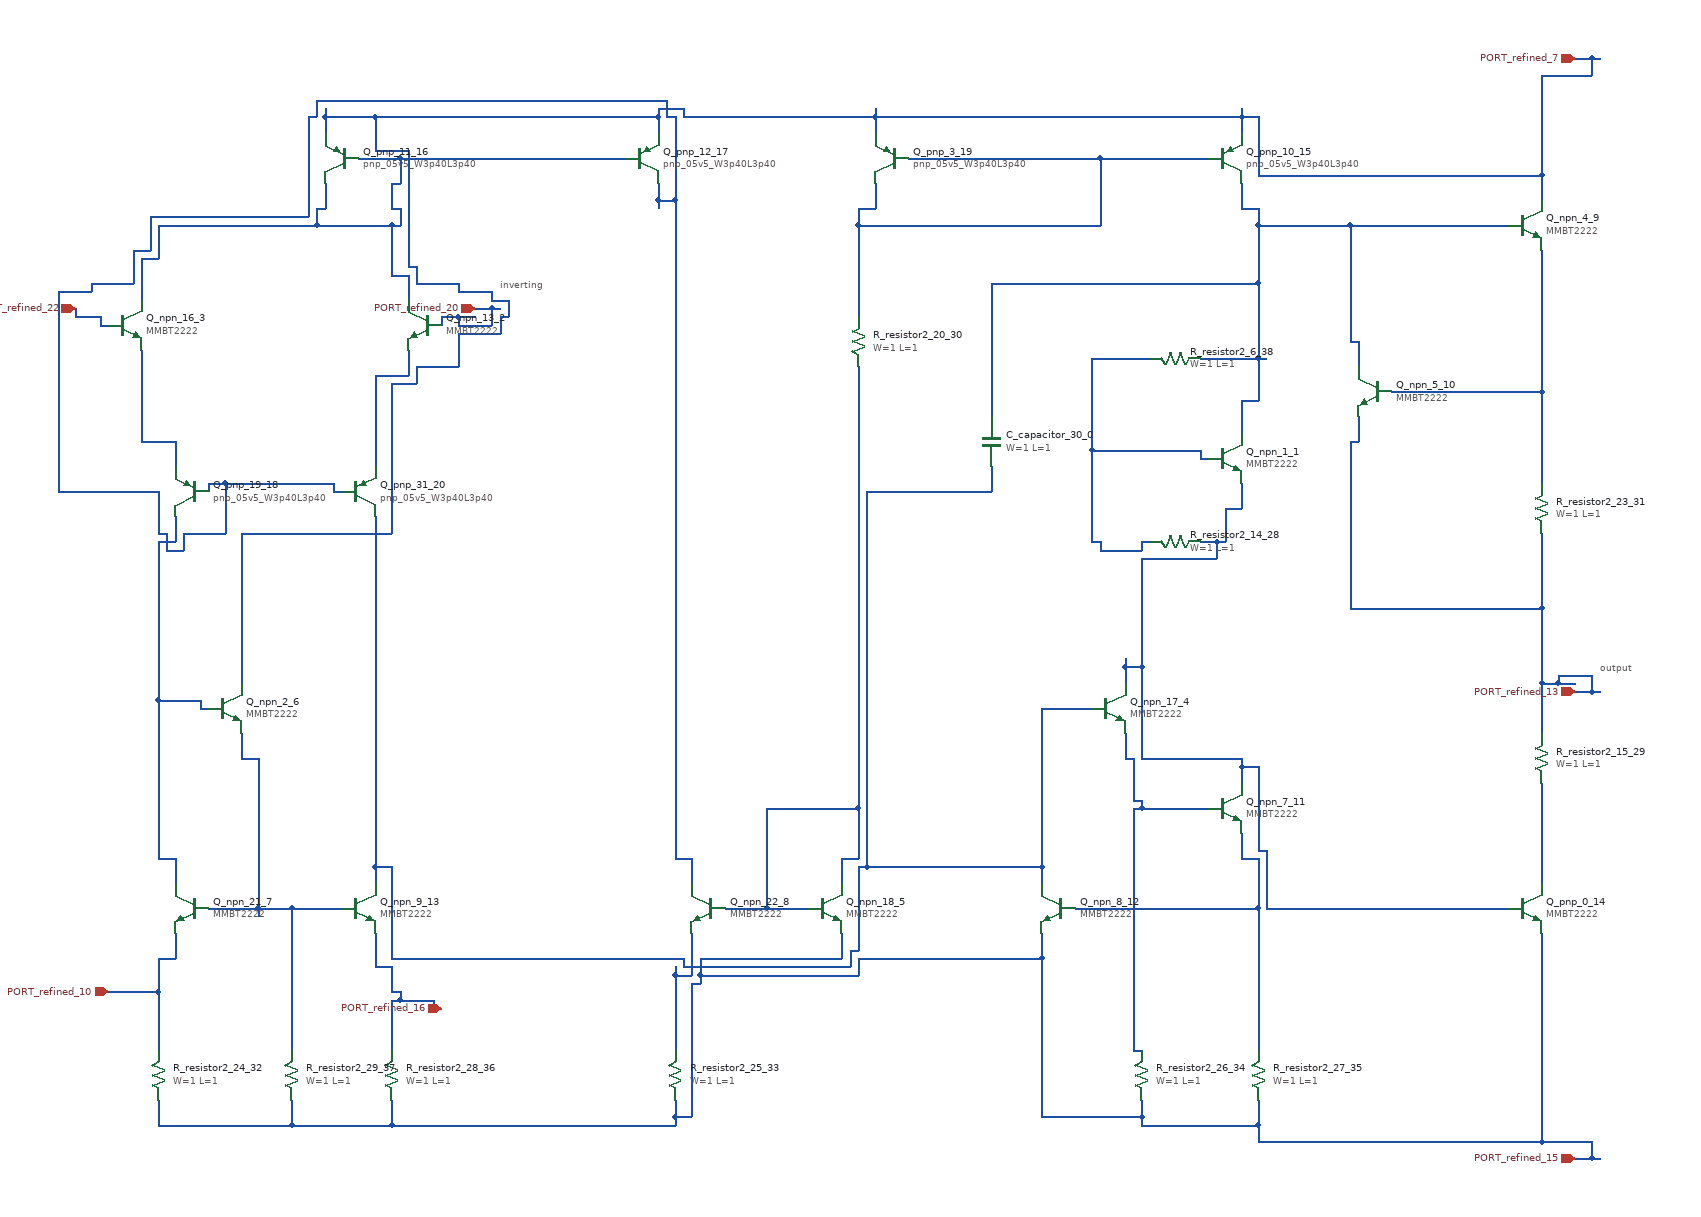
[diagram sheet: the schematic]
v {xschem version=3.4.8 file_version=1.2}
G {}
K {}
V {}
S {}
E {}
C {sky130_fd_pr/cap_mim_m3_1.sym} 1320 520 2 0 {name="C_capacitor_30_0" model=cap_mim_m3_1 W=1 L=1 MF=1 spiceprefix=X}
C {devices/npn.sym} 1600 540 0 0 {name="Q_npn_1_1"
model=MMBT2222
device=MMBT2222
footprint=SOT23
area=1
m=1}
C {devices/npn.sym} 640 380 0 1 {name="Q_npn_13_2"
model=MMBT2222
device=MMBT2222
footprint=SOT23
area=1
m=1}
C {devices/npn.sym} 280 380 0 0 {name="Q_npn_16_3"
model=MMBT2222
device=MMBT2222
footprint=SOT23
area=1
m=1}
C {devices/npn.sym} 1460 840 0 0 {name="Q_npn_17_4"
model=MMBT2222
device=MMBT2222
footprint=SOT23
area=1
m=1}
C {devices/npn.sym} 1120 1080 0 0 {name="Q_npn_18_5"
model=MMBT2222
device=MMBT2222
footprint=SOT23
area=1
m=1}
C {devices/npn.sym} 400 840 0 0 {name="Q_npn_2_6"
model=MMBT2222
device=MMBT2222
footprint=SOT23
area=1
m=1}
C {devices/npn.sym} 360 1080 0 1 {name="Q_npn_21_7"
model=MMBT2222
device=MMBT2222
footprint=SOT23
area=1
m=1}
C {devices/npn.sym} 980 1080 0 1 {name="Q_npn_22_8"
model=MMBT2222
device=MMBT2222
footprint=SOT23
area=1
m=1}
C {devices/npn.sym} 1960 260 0 0 {name="Q_npn_4_9"
model=MMBT2222
device=MMBT2222
footprint=SOT23
area=1
m=1}
C {devices/npn.sym} 1780 460 0 1 {name="Q_npn_5_10"
model=MMBT2222
device=MMBT2222
footprint=SOT23
area=1
m=1}
C {devices/npn.sym} 1600 960 0 0 {name="Q_npn_7_11"
model=MMBT2222
device=MMBT2222
footprint=SOT23
area=1
m=1}
C {devices/npn.sym} 1400 1080 0 1 {name="Q_npn_8_12"
model=MMBT2222
device=MMBT2222
footprint=SOT23
area=1
m=1}
C {devices/npn.sym} 560 1080 0 0 {name="Q_npn_9_13"
model=MMBT2222
device=MMBT2222
footprint=SOT23
area=1
m=1}
C {devices/npn.sym} 1960 1080 0 0 {name="Q_pnp_0_14"
model=MMBT2222
device=MMBT2222
footprint=SOT23
area=1
m=1}
C {sky130_fd_pr/pnp_05v5.sym} 1600 180 0 0 {name="Q_pnp_10_15"
model=pnp_05v5_W3p40L3p40
m=1
spiceprefix=X
}
C {sky130_fd_pr/pnp_05v5.sym} 540 180 0 1 {name="Q_pnp_11_16"
model=pnp_05v5_W3p40L3p40
m=1
spiceprefix=X
}
C {sky130_fd_pr/pnp_05v5.sym} 900 180 0 0 {name="Q_pnp_12_17"
model=pnp_05v5_W3p40L3p40
m=1
spiceprefix=X
}
C {sky130_fd_pr/pnp_05v5.sym} 360 580 0 1 {name="Q_pnp_19_18"
model=pnp_05v5_W3p40L3p40
m=1
spiceprefix=X
}
C {sky130_fd_pr/pnp_05v5.sym} 1200 180 0 1 {name="Q_pnp_3_19"
model=pnp_05v5_W3p40L3p40
m=1
spiceprefix=X
}
C {sky130_fd_pr/pnp_05v5.sym} 560 580 0 0 {name="Q_pnp_31_20"
model=pnp_05v5_W3p40L3p40
m=1
spiceprefix=X
}
C {devices/ipin.sym} 2020 60 0 0 {name="p_port_32_21" lab="PORT_refined_7"}
C {devices/ipin.sym} 260 1180 0 0 {name="p_port_33_22" lab="PORT_refined_10"}
C {devices/ipin.sym} 2020 1380 0 0 {name="p_port_34_23" lab="PORT_refined_15"}
C {devices/ipin.sym} 220 360 0 0 {name="p_port_35_24" lab="PORT_refined_22"}
C {devices/ipin.sym} 660 1200 0 0 {name="p_port_36_25" lab="PORT_refined_16"}
C {devices/ipin.sym} 700 360 0 0 {name="p_port_40_26" lab="PORT_refined_20"}
T {inverting} 730 320 0 0 0.25 0.25 {}
C {devices/ipin.sym} 2020 820 0 0 {name="p_port_41_27" lab="PORT_refined_13"}
T {output} 2050 780 0 0 0.25 0.25 {}
C {sky130_fd_pr/res_generic_po.sym} 1540 640 1 0 {name="R_resistor2_14_28"
W=1
L=1
model=res_generic_po
spiceprefix=X
mult=1}
C {sky130_fd_pr/res_generic_po.sym} 1980 900 2 0 {name="R_resistor2_15_29"
W=1
L=1
model=res_generic_po
spiceprefix=X
mult=1}
C {sky130_fd_pr/res_generic_po.sym} 1160 400 2 0 {name="R_resistor2_20_30"
W=1
L=1
model=res_generic_po
spiceprefix=X
mult=1}
C {sky130_fd_pr/res_generic_po.sym} 1980 600 2 0 {name="R_resistor2_23_31"
W=1
L=1
model=res_generic_po
spiceprefix=X
mult=1}
C {sky130_fd_pr/res_generic_po.sym} 320 1280 2 0 {name="R_resistor2_24_32"
W=1
L=1
model=res_generic_po
spiceprefix=X
mult=1}
C {sky130_fd_pr/res_generic_po.sym} 940 1280 2 0 {name="R_resistor2_25_33"
W=1
L=1
model=res_generic_po
spiceprefix=X
mult=1}
C {sky130_fd_pr/res_generic_po.sym} 1500 1280 2 0 {name="R_resistor2_26_34"
W=1
L=1
model=res_generic_po
spiceprefix=X
mult=1}
C {sky130_fd_pr/res_generic_po.sym} 1640 1280 2 0 {name="R_resistor2_27_35"
W=1
L=1
model=res_generic_po
spiceprefix=X
mult=1}
C {sky130_fd_pr/res_generic_po.sym} 600 1280 2 0 {name="R_resistor2_28_36"
W=1
L=1
model=res_generic_po
spiceprefix=X
mult=1}
C {sky130_fd_pr/res_generic_po.sym} 480 1280 2 0 {name="R_resistor2_29_37"
W=1
L=1
model=res_generic_po
spiceprefix=X
mult=1}
C {sky130_fd_pr/res_generic_po.sym} 1540 420 1 0 {name="R_resistor2_6_38"
W=1
L=1
model=res_generic_po
spiceprefix=X
mult=1}
N 1620 470 1640 470 {}
N 1570 420 1640 420 {}
N 1640 420 1650 420 {}
N 1750 400 1760 400 {}
N 1320 330 1640 330 {}
N 1640 260 1750 260 {}
N 1750 260 1940 260 {}
N 1620 240 1640 240 {}
N 1320 510 1320 490 {}
N 1320 490 1320 330 {}
N 1620 510 1620 470 {}
N 1620 240 1620 210 {}
N 1640 470 1640 420 {}
N 1640 420 1640 330 {}
N 1640 330 1640 260 {}
N 1640 260 1640 240 {}
N 1750 400 1750 260 {}
N 1760 430 1760 400 {}
N 950 1150 1150 1150 {}
N 600 1140 950 1140 {}
N 1150 1130 1160 1130 {}
N 580 1030 600 1030 {}
N 1160 1030 1170 1030 {}
N 1170 1030 1380 1030 {}
N 1380 840 1440 840 {}
N 1170 580 1320 580 {}
N 580 1050 580 1030 {}
N 580 1030 580 610 {}
N 600 1140 600 1030 {}
N 950 1150 950 1140 {}
N 1150 1150 1150 1130 {}
N 1160 1130 1160 1030 {}
N 1170 1030 1170 580 {}
N 1320 580 1320 550 {}
N 1380 1050 1380 1030 {}
N 1380 1030 1380 840 {}
N 260 1180 320 1180 {}
N 320 1140 340 1140 {}
N 320 1250 320 1180 {}
N 320 1180 320 1140 {}
N 340 1140 340 1110 {}
N 940 1160 960 1160 {}
N 940 1250 940 1160 {}
N 940 1160 940 1150 {}
N 960 1160 960 1110 {}
N 1800 460 1980 460 {}
N 1980 570 1980 460 {}
N 1980 460 1980 290 {}
N 2020 820 2040 820 {}
N 2040 820 2050 820 {}
N 1980 810 2000 810 {}
N 2000 810 2020 810 {}
N 2000 800 2040 800 {}
N 1750 720 1980 720 {}
N 1750 520 1760 520 {}
N 1750 720 1750 520 {}
N 1760 520 1760 490 {}
N 1980 870 1980 810 {}
N 1980 810 1980 720 {}
N 1980 720 1980 630 {}
N 2000 810 2000 800 {}
N 2040 820 2040 800 {}
N 1420 1080 1640 1080 {}
N 1620 1020 1640 1020 {}
N 1620 1020 1620 990 {}
N 1640 1250 1640 1080 {}
N 1640 1080 1640 1020 {}
N 2020 1380 2040 1380 {}
N 2040 1380 2050 1380 {}
N 1640 1360 1980 1360 {}
N 1980 1360 2040 1360 {}
N 320 1340 480 1340 {}
N 480 1340 600 1340 {}
N 600 1340 940 1340 {}
N 1500 1340 1640 1340 {}
N 940 1330 960 1330 {}
N 1380 1330 1500 1330 {}
N 960 1170 970 1170 {}
N 970 1160 1160 1160 {}
N 970 1140 1140 1140 {}
N 1160 1140 1380 1140 {}
N 320 1340 320 1310 {}
N 480 1340 480 1310 {}
N 600 1340 600 1310 {}
N 940 1340 940 1330 {}
N 940 1330 940 1310 {}
N 960 1330 960 1170 {}
N 970 1170 970 1160 {}
N 970 1160 970 1140 {}
N 1140 1140 1140 1110 {}
N 1160 1160 1160 1140 {}
N 1380 1330 1380 1140 {}
N 1380 1140 1380 1110 {}
N 1500 1340 1500 1330 {}
N 1500 1330 1500 1310 {}
N 1640 1360 1640 1340 {}
N 1640 1340 1640 1310 {}
N 1980 1360 1980 1110 {}
N 2040 1380 2040 1360 {}
N 650 1200 660 1200 {}
N 600 1190 610 1190 {}
N 610 1190 650 1190 {}
N 600 1180 610 1180 {}
N 580 1150 600 1150 {}
N 580 1150 580 1110 {}
N 600 1250 600 1190 {}
N 600 1180 600 1150 {}
N 610 1190 610 1180 {}
N 650 1200 650 1190 {}
N 1980 1050 1980 930 {}
N 1160 260 1450 260 {}
N 1160 240 1180 240 {}
N 1220 180 1450 180 {}
N 1450 180 1580 180 {}
N 1160 370 1160 260 {}
N 1160 260 1160 240 {}
N 1180 240 1180 210 {}
N 1450 260 1450 180 {}
N 600 320 620 320 {}
N 300 300 320 300 {}
N 320 260 510 260 {}
N 510 260 600 260 {}
N 600 260 610 260 {}
N 510 240 520 240 {}
N 600 240 610 240 {}
N 600 210 610 210 {}
N 560 180 610 180 {}
N 610 180 880 180 {}
N 300 350 300 300 {}
N 320 300 320 260 {}
N 510 260 510 240 {}
N 520 240 520 210 {}
N 600 320 600 260 {}
N 600 240 600 210 {}
N 610 260 610 240 {}
N 610 210 610 180 {}
N 620 350 620 320 {}
N 300 520 340 520 {}
N 300 520 300 410 {}
N 340 550 340 520 {}
N 680 380 720 380 {}
N 660 370 680 370 {}
N 680 370 700 370 {}
N 700 360 720 360 {}
N 720 360 730 360 {}
N 660 380 660 370 {}
N 680 380 680 370 {}
N 720 380 720 360 {}
N 580 440 620 440 {}
N 580 550 580 440 {}
N 620 440 620 410 {}
N 250 380 260 380 {}
N 220 370 250 370 {}
N 220 370 220 360 {}
N 250 380 250 370 {}
N 940 1020 960 1020 {}
N 330 650 350 650 {}
N 320 630 330 630 {}
N 350 630 400 630 {}
N 200 580 320 580 {}
N 530 580 540 580 {}
N 380 570 400 570 {}
N 400 570 530 570 {}
N 200 340 240 340 {}
N 240 330 290 330 {}
N 290 290 310 290 {}
N 310 250 500 250 {}
N 920 230 940 230 {}
N 500 130 510 130 {}
N 930 130 940 130 {}
N 510 110 930 110 {}
N 200 580 200 340 {}
N 240 340 240 330 {}
N 290 330 290 290 {}
N 310 290 310 250 {}
N 320 630 320 580 {}
N 330 650 330 630 {}
N 350 650 350 630 {}
N 380 580 380 570 {}
N 400 630 400 570 {}
N 500 250 500 130 {}
N 510 130 510 110 {}
N 530 580 530 570 {}
N 920 240 920 230 {}
N 920 230 920 210 {}
N 930 130 930 110 {}
N 940 1020 940 230 {}
N 940 230 940 130 {}
N 960 1050 960 1020 {}
N 1650 1080 1940 1080 {}
N 1640 1010 1650 1010 {}
N 1620 910 1640 910 {}
N 1500 900 1620 900 {}
N 1480 790 1500 790 {}
N 1500 660 1590 660 {}
N 1570 640 1590 640 {}
N 1590 640 1600 640 {}
N 1600 600 1620 600 {}
N 1480 810 1480 790 {}
N 1480 790 1480 780 {}
N 1500 900 1500 790 {}
N 1500 790 1500 660 {}
N 1590 660 1590 640 {}
N 1600 640 1600 600 {}
N 1620 930 1620 910 {}
N 1620 910 1620 900 {}
N 1620 600 1620 570 {}
N 1640 1010 1640 910 {}
N 1650 1080 1650 1010 {}
N 1490 1250 1500 1250 {}
N 1490 960 1500 960 {}
N 1500 960 1580 960 {}
N 1490 950 1500 950 {}
N 1480 900 1490 900 {}
N 1480 900 1480 870 {}
N 1490 1250 1490 960 {}
N 1490 950 1490 900 {}
N 1500 960 1500 950 {}
N 1000 1080 1050 1080 {}
N 1050 1080 1100 1080 {}
N 1140 1020 1160 1020 {}
N 1050 960 1160 960 {}
N 1050 1080 1050 960 {}
N 1140 1050 1140 1020 {}
N 1160 1020 1160 960 {}
N 1160 960 1160 430 {}
N 320 1020 340 1020 {}
N 370 840 380 840 {}
N 320 830 370 830 {}
N 320 640 340 640 {}
N 320 1020 320 830 {}
N 320 830 320 640 {}
N 340 1050 340 1020 {}
N 340 640 340 610 {}
N 370 840 370 830 {}
N 420 630 600 630 {}
N 600 450 630 450 {}
N 630 430 680 430 {}
N 680 390 730 390 {}
N 730 370 740 370 {}
N 720 350 740 350 {}
N 680 340 720 340 {}
N 630 330 680 330 {}
N 620 310 630 310 {}
N 1640 200 1980 200 {}
N 580 170 620 170 {}
N 520 130 580 130 {}
N 580 130 920 130 {}
N 950 130 1180 130 {}
N 1180 130 1620 130 {}
N 1620 130 1640 130 {}
N 920 120 950 120 {}
N 1980 80 2040 80 {}
N 2020 60 2040 60 {}
N 2040 60 2050 60 {}
N 420 810 420 630 {}
N 520 150 520 130 {}
N 520 130 520 120 {}
N 580 170 580 130 {}
N 600 630 600 450 {}
N 620 310 620 170 {}
N 630 450 630 430 {}
N 630 330 630 310 {}
N 680 430 680 390 {}
N 680 340 680 330 {}
N 720 350 720 340 {}
N 730 390 730 370 {}
N 740 370 740 350 {}
N 920 150 920 130 {}
N 920 130 920 120 {}
N 950 130 950 120 {}
N 1180 150 1180 130 {}
N 1180 130 1180 120 {}
N 1620 150 1620 130 {}
N 1620 130 1620 120 {}
N 1640 200 1640 130 {}
N 1980 230 1980 200 {}
N 1980 200 1980 80 {}
N 2040 80 2040 60 {}
N 380 1080 440 1080 {}
N 440 1080 480 1080 {}
N 480 1080 540 1080 {}
N 420 900 440 900 {}
N 420 900 420 870 {}
N 440 1090 440 1080 {}
N 440 1080 440 900 {}
N 480 1250 480 1080 {}
N 1450 650 1500 650 {}
N 1440 640 1450 640 {}
N 1500 640 1510 640 {}
N 1570 540 1580 540 {}
N 1440 530 1570 530 {}
N 1440 420 1510 420 {}
N 1440 640 1440 530 {}
N 1440 530 1440 420 {}
N 1450 650 1450 640 {}
N 1500 650 1500 640 {}
N 1570 540 1570 530 {}
